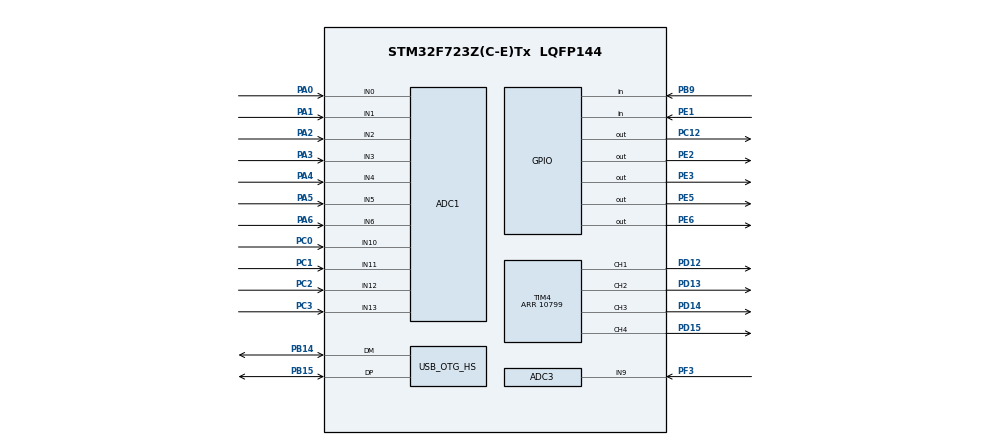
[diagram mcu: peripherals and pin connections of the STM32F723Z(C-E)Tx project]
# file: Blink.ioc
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ADC1.Channel-10\#ChannelRegularConversion=ADC_CHANNEL_2
ADC1.Channel-11\#ChannelRegularConversion=ADC_CHANNEL_3
ADC1.Channel-12\#ChannelRegularConversion=ADC_CHANNEL_4
ADC1.Channel-13\#ChannelRegularConversion=ADC_CHANNEL_5
ADC1.Channel-14\#ChannelRegularConversion=ADC_CHANNEL_10
ADC1.Channel-15\#ChannelRegularConversion=ADC_CHANNEL_11
ADC1.Channel-16\#ChannelRegularConversion=ADC_CHANNEL_12
ADC1.Channel-17\#ChannelRegularConversion=ADC_CHANNEL_6
ADC1.Channel-8\#ChannelRegularConversion=ADC_CHANNEL_0
ADC1.Channel-9\#ChannelRegularConversion=ADC_CHANNEL_1
ADC1.ClockPrescaler=ADC_CLOCK_SYNC_PCLK_DIV8
ADC1.ContinuousConvMode=ENABLE
ADC1.DMAContinuousRequests=ENABLE
ADC1.EOCSelection=ADC_EOC_SEQ_CONV
ADC1.ExternalTrigConv=ADC_SOFTWARE_START
ADC1.InjNumberOfConversion=0
ADC1.NbrOfConversion=10
ADC1.NbrOfConversionFlag=1
ADC1.Rank-10\#ChannelRegularConversion=3
ADC1.Rank-11\#ChannelRegularConversion=4
ADC1.Rank-12\#ChannelRegularConversion=5
ADC1.Rank-13\#ChannelRegularConversion=6
ADC1.Rank-14\#ChannelRegularConversion=7
ADC1.Rank-15\#ChannelRegularConversion=8
ADC1.Rank-16\#ChannelRegularConversion=9
ADC1.Rank-17\#ChannelRegularConversion=10
ADC1.Rank-8\#ChannelRegularConversion=1
ADC1.Rank-9\#ChannelRegularConversion=2
ADC1.SamplingTime-10\#ChannelRegularConversion=ADC_SAMPLETIME_3CYCLES
ADC1.SamplingTime-11\#ChannelRegularConversion=ADC_SAMPLETIME_3CYCLES
ADC1.SamplingTime-12\#ChannelRegularConversion=ADC_SAMPLETIME_3CYCLES
ADC1.SamplingTime-13\#ChannelRegularConversion=ADC_SAMPLETIME_3CYCLES
ADC1.SamplingTime-14\#ChannelRegularConversion=ADC_SAMPLETIME_3CYCLES
ADC1.SamplingTime-15\#ChannelRegularConversion=ADC_SAMPLETIME_3CYCLES
ADC1.SamplingTime-16\#ChannelRegularConversion=ADC_SAMPLETIME_3CYCLES
ADC1.SamplingTime-17\#ChannelRegularConversion=ADC_SAMPLETIME_3CYCLES
ADC1.SamplingTime-8\#ChannelRegularConversion=ADC_SAMPLETIME_3CYCLES
ADC1.SamplingTime-9\#ChannelRegularConversion=ADC_SAMPLETIME_3CYCLES
ADC1.master=1
ADC3.Channel-1\#ChannelRegularConversion=ADC_CHANNEL_9
ADC3.ClockPrescaler=ADC_CLOCK_SYNC_PCLK_DIV8
ADC3.NbrOfConversionFlag=1
ADC3.Rank-1\#ChannelRegularConversion=1
ADC3.SamplingTime-1\#ChannelRegularConversion=ADC_SAMPLETIME_3CYCLES
CORTEX_M7.default_mode_Activation=1
Dma.ADC1.0.Direction=DMA_PERIPH_TO_MEMORY
Dma.ADC1.0.FIFOMode=DMA_FIFOMODE_DISABLE
Dma.ADC1.0.Instance=DMA2_Stream0
Dma.ADC1.0.MemDataAlignment=DMA_MDATAALIGN_HALFWORD
Dma.ADC1.0.MemInc=DMA_MINC_ENABLE
Dma.ADC1.0.Mode=DMA_CIRCULAR
Dma.ADC1.0.PeriphDataAlignment=DMA_PDATAALIGN_HALFWORD
Dma.ADC1.0.PeriphInc=DMA_PINC_DISABLE
Dma.ADC1.0.Priority=DMA_PRIORITY_LOW
Dma.Request0=ADC1
Mcu.Family=STM32F7
Mcu.Name=STM32F723Z(C-E)Tx
Mcu.Package=LQFP144
NVIC.ADC_IRQn=true\:0\:0\:false\:false\:true\:true\:true\:true
NVIC.DMA2_Stream0_IRQn=true\:0\:0\:false\:false\:true\:false\:true\:true
NVIC.OTG_HS_IRQn=true\:0\:0\:false\:false\:true\:true\:true\:true
NVIC.PriorityGroup=NVIC_PRIORITYGROUP_4
NVIC.TIM2_IRQn=true\:0\:0\:false\:false\:true\:true\:true\:true
NVIC.TIM5_IRQn=true\:0\:0\:false\:false\:true\:true\:true\:true
PA0-WKUP.Signal=ADCx_IN0
PA1.Signal=ADCx_IN1
PA13.Mode=Serial_Wire
PA13.Signal=SYS_JTMS-SWDIO
PA14.Mode=Serial_Wire
PA14.Signal=SYS_JTCK-SWCLK
PA2.Signal=ADCx_IN2
PA3.Signal=ADCx_IN3
PA4.Signal=ADCx_IN4
PA5.Signal=ADCx_IN5
PA6.Signal=ADCx_IN6
PB0.Signal=ADCx_IN8
PB14.Mode=Internal_Phy_Device
PB14.Signal=USB_OTG_HS_DM
PB15.Mode=Internal_Phy_Device
PB15.Signal=USB_OTG_HS_DP
PB9.GPIO_PuPd=GPIO_PULLDOWN
PB9.Signal=GPIO_Input
PC0.Signal=ADCx_IN10
PC1.Signal=ADCx_IN11
PC12.Signal=GPIO_Output
PC2.Signal=ADCx_IN12
PC3.Signal=ADCx_IN13
PC4.Signal=ADCx_IN14
PD12.Signal=S_TIM4_CH1
PD13.Signal=S_TIM4_CH2
PD14.Signal=S_TIM4_CH3
PD15.Signal=S_TIM4_CH4
PE1.GPIO_PuPd=GPIO_PULLDOWN
PE1.Signal=GPIO_Input
PE2.Signal=GPIO_Output
PE3.Signal=GPIO_Output
PE5.Signal=GPIO_Output
PE6.Signal=GPIO_Output
PF3.Mode=IN9
PF3.Signal=ADC3_IN9
PH0-OSC_IN.Mode=HSE-External-Oscillator
PH0-OSC_IN.Signal=RCC_OSC_IN
PH1-OSC_OUT.Mode=HSE-External-Oscillator
PH1-OSC_OUT.Signal=RCC_OSC_OUT
ProjectManager.HeapSize=0x200
ProjectManager.StackSize=0x400
ProjectManager.TargetToolchain=Makefile
RCC.AHBFreq_Value=96000000
RCC.APB1CLKDivider=RCC_HCLK_DIV2
RCC.APB1Freq_Value=48000000
RCC.APB1TimFreq_Value=96000000
RCC.APB2Freq_Value=96000000
RCC.APB2TimFreq_Value=96000000
RCC.CortexFreq_Value=96000000
RCC.HCLKFreq_Value=96000000
RCC.HSE_VALUE=12000000
RCC.HSI_VALUE=16000000
RCC.LSE_VALUE=32768
RCC.PLLM=6
RCC.PLLN=96
RCC.PLLQ=4
RCC.SYSCLKFreq_VALUE=96000000
RCC.SYSCLKSource=RCC_SYSCLKSOURCE_PLLCLK
RCC.USBFreq_Value=48000000
RCC.VCOOutputFreq_Value=192000000
REXTPHYHS.Mode=Internal_Phy_Device
REXTPHYHS.Signal=USB_OTG_HS_REXTPHYHS
SH.ADCx_IN0.0=ADC1_IN0,IN0
SH.ADCx_IN1.0=ADC1_IN1,IN1
SH.ADCx_IN10.0=ADC1_IN10,IN10
SH.ADCx_IN11.0=ADC1_IN11,IN11
SH.ADCx_IN12.0=ADC1_IN12,IN12
SH.ADCx_IN13.0=ADC1_IN13,IN13
SH.ADCx_IN14.0=ADC1_IN14
SH.ADCx_IN2.0=ADC1_IN2,IN2
SH.ADCx_IN3.0=ADC2_IN3
SH.ADCx_IN3.1=ADC1_IN3,IN3
SH.ADCx_IN4.0=ADC2_IN4
SH.ADCx_IN4.1=ADC1_IN4,IN4
SH.ADCx_IN5.0=ADC1_IN5,IN5
SH.ADCx_IN6.0=ADC1_IN6,IN6
SH.ADCx_IN8.0=ADC1_IN8
SH.S_TIM4_CH1.0=TIM4_CH1,PWM Generation1 CH1
SH.S_TIM4_CH2.0=TIM4_CH2,PWM Generation2 CH2
SH.S_TIM4_CH3.0=TIM4_CH3,PWM Generation3 CH3
SH.S_TIM4_CH4.0=TIM4_CH4,PWM Generation4 CH4
TIM2.Period=5399
TIM4.Channel-PWM\ Generation1\ CH1=TIM_CHANNEL_1
TIM4.Channel-PWM\ Generation2\ CH2=TIM_CHANNEL_2
TIM4.Channel-PWM\ Generation3\ CH3=TIM_CHANNEL_3
TIM4.Channel-PWM\ Generation4\ CH4=TIM_CHANNEL_4
TIM4.Period=10799
TIM5.Period=216000
TIM5.TIM_MasterOutputTrigger=TIM_TRGO_UPDATE
USB_OTG_HS.VirtualMode=Int_Phy_Device
VP_TIM2_VS_ClockSourceINT.Mode=Internal
VP_TIM5_VS_ClockSourceINT.Mode=Internal
board=custom

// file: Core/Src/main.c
/* USER CODE BEGIN Header */
/**
  ******************************************************************************
  * @file           : main.c
  * @brief          : Main program body
  ******************************************************************************
  * @attention
  *
  * Copyright (c) 2024 STMicroelectronics.
  * All rights reserved.
  *
  * This software is licensed under terms that can be found in the LICENSE file
  * in the root directory of this software component.
  * If no LICENSE file comes with this software, it is provided AS-IS.
  *
  ******************************************************************************
  */
/* USER CODE END Header */
#include "main.h"

/* USER CODE BEGIN Includes */

#include "device/usbd_pvt.h"
#include "stm32f7xx_hal_adc.h"
#include "stm32f7xx_hal_def.h"

#include "motor.h"
#include "controller.h"
#include "stm32f7xx_hal_tim.h"

#include "arm_math.h"
#include <stdint.h>

#include "tusb_config.h"
#include "tusb.h"
#include "SEGGER_RTT.h"

/* USER CODE END Includes */

ADC_HandleTypeDef hadc1;
ADC_HandleTypeDef hadc3;
DMA_HandleTypeDef hdma_adc1;

TIM_HandleTypeDef htim2;
TIM_HandleTypeDef htim4;
TIM_HandleTypeDef htim5;

PCD_HandleTypeDef hpcd_USB_OTG_HS;

/* USER CODE BEGIN PV */

// DELETE SOON

// float pwmCommand1 = 0;
// float current1 = 0;
// const float k = 0.34/6.9;
// float T1_Read;
// float T1_Set;
// float error;
float theta1;
float theta2;
float current1;
float current2;
float W1;
float W2;
float pwm1;
float pwm2;
float pwm_command;

volatile float torqueSet;
float T2;
float T3;

//Grav Comp on/off 1/0
commands_t controllerStatus;

//text

// Variable Definition

/* USER CODE END PV */

void SystemClock_Config(void);
static void MPU_Config(void);
static void MX_GPIO_Init(void);
static void MX_DMA_Init(void);
static void MX_ADC3_Init(void);
static void MX_TIM4_Init(void);
static void MX_ADC1_Init(void);
static void MX_TIM2_Init(void);
static void MX_TIM5_Init(void);
static void MX_USB_OTG_HS_PCD_Init(void);
/* USER CODE BEGIN PFP */
int16_t DMA_buffer[10];

// CONTROLLER
controller_t controller1 = {
  .J1 =
  {

  .htim = &htim4,
  .pwm_channel = TIM_CHANNEL_4,
  .dir_port = GPIOE,
  .motorDir = 1,
  .dir_pin = GPIO_PIN_3,
  .fault_port = GPIOE,
  .fault_pin = GPIO_PIN_2,

  .positionCounts = &DMA_buffer[3],
  .currentCounts = &DMA_buffer[6],

  .angle_range = -45.0f,
  .angle_start = 2053.0f,
  .angle_end = 1480.0f,

  .Rsense = 0.01081,
  .frictionGain = 0.8127,
  .frictionOffset = 1.6,

   .pid =
    {
      .kp = 0.01,
      .ki = 0.02,
      .kd = 0,
      .processMax = 1,
      .processMin = 0
    }
  },

  .J2 =
  {
  .htim = &htim4,
  .pwm_channel = TIM_CHANNEL_4,
  .dir_port = GPIOE,
  .dir_pin = GPIO_PIN_3,
  .motorDir = 1,
  .fault_port = GPIOE,
  .fault_pin = GPIO_PIN_2,

  .positionCounts = &DMA_buffer[0],
  .currentCounts = &DMA_buffer[6],

  .Rsense = 0.01752467,
  .frictionGain = 0.1473,
  .frictionOffset = 1.1673,

  .angle_range = 90.0f,
  .angle_start = 2051.0f,
  .angle_end = 964.0f,

  .pid =
    {
      .kp = 0.01,
      .ki = 0.02,
      .kd = 0,
      .processMax = 1,
      .processMin = 0.01
    }
  },

  .J3 =
  {
  .htim = &htim4,
  .pwm_channel = TIM_CHANNEL_2,
  .dir_port = GPIOC,
  .dir_pin = GPIO_PIN_15,
  .motorDir = 1,

  .positionCounts = &DMA_buffer[2],
  .currentCounts = &DMA_buffer[8],

  .Rsense = 0.019512,
  .frictionGain = 0.1946,
  .frictionOffset = 0.86,

  .angle_range = -90.0f,
  .angle_start = 3087.0f,
  .angle_end = 2066.0f,

  .pid =
    {
      .kp = 0.01,
      .ki = 0.02,
      .kd = 0,
      .processMax = 1,
      .processMin = 0.01
    }
  },

  .J4 =
  {
  .htim = &htim4,
  .pwm_channel = TIM_CHANNEL_1,
  .dir_port = GPIOF,
  .dir_pin = GPIO_PIN_2,
  .motorDir = 1,

  .positionCounts = &DMA_buffer[4],

  .angle_range = -90.0f,
  .angle_start = 1719.0f,
  .angle_end = 605.0f,

  // .pid =
  //   {
  //     .kp = 0.3,
  //     .ki = 0.01,
  //     .kd = 0,
  //     .processMax = 1,
  //     .processMin = 0.01
  //   }
  },

  .J5 =
  {
  .htim = &htim4,
  .pwm_channel = TIM_CHANNEL_2,
  .dir_port = GPIOE,
  .dir_pin = GPIO_PIN_6,

  .positionCounts = &DMA_buffer[4],
  // .currentCounts = &DMA_buffer[12],

  // .theta_current = 0,
  // .angle_range = -90.0f,
  // .angle_start = 1012.0f,
  // .angle_end = 1977.0f,

  // .pid =
  //   {
  //     .kp = 0.3,
  //     .ki = 0.01,
  //     .kd = 0,
  //     .processMax = 1,
  //     .processMin = 0.01
  //   }
  },

  .J6 =
  {
  // .htim = &htim4,
  // .pwm_channel = TIM_CHANNEL_2,
  // .dir_port = GPIOE,
  // .dir_pin = GPIO_PIN_6,

  .positionCounts = &DMA_buffer[5],
  // .currentCounts = &DMA_buffer[12],

  // .theta_current = 0,
  // .angle_range = -90.0f,
  // .angle_start = 1012.0f,
  // .angle_end = 1977.0f,

  // .pid =
  //   {
  //     .kp = 0.3,
  //     .ki = 0.01,
  //     .kd = 0,
  //     .processMax = 1,
  //     .processMin = 0.01
  //   }
  },
  .gc_scale_T2 = 0.4,
  .gc_scale_T3 = 0.4,

  //Button Inputs
  .raw_trigger_reading = &DMA_buffer[5],
  .clutch_port = GPIOB,
  .clutch_pin = GPIO_PIN_9,
  .trigger_on = 2000.0f,
  .trigger_zero = 2400.0f,

  .frameScale = 0.3,

  .homeX = 0,
  .homeY = 0,
  .homeZ = 370.0f,

  .miraXoff = 0,
  .miraYoff = -28,
  .miraZoff = -50,

  .pitchOffset = 15.0

};

/* USER CODE END PFP */

/* USER CODE BEGIN 0 */

// // Function - USB Blocking
// USBD_StatusTypeDef CDC_Transmit_HS_Blocking(uint8_t* Buf, uint16_t Len) {
//     USBD_StatusTypeDef result = USBD_BUSY;

//     // Keep attempting to transmit until USBD_OK is returned
//     while (result != USBD_OK) {
//         result = CDC_Transmit_HS(Buf, Len);

//         // Optionally add a small delay to avoid CPU overload
//         HAL_Delay(1);
//     }

//     return result;
// }
uint8_t rtt_buffer[1024];

typedef struct {

  commands_t gc_status;

  // float j1_torque;
  // float j2_torque;
  // float j3_torque;
} setpoint_cmd_t;

typedef struct __attribute__((packed)) {
  float x;
  float y;
  float z;
  float pitch;
  float trigger;

  uint8_t clutch_status;

} armstatus_t;

/* USER CODE END 0 */

int main(void)
{

  /* USER CODE BEGIN 1 */
  SEGGER_RTT_ConfigUpBuffer(0, NULL, rtt_buffer, sizeof(rtt_buffer), SEGGER_RTT_MODE_NO_BLOCK_SKIP);

  printf("hello again");
  /* USER CODE END 1 */

  /* MPU Configuration--------------------------------------------------------*/
  MPU_Config();

  /* MCU Configuration--------------------------------------------------------*/

  /* Reset of all peripherals, Initializes the Flash interface and the Systick. */
  HAL_Init();

  /* Configure the system clock */
  SystemClock_Config();

  /* Initialize all configured peripherals */
  MX_GPIO_Init();
  MX_DMA_Init();
  MX_ADC3_Init();
  MX_TIM4_Init();
  MX_ADC1_Init();
  MX_TIM2_Init();
  MX_TIM5_Init();
  MX_USB_OTG_HS_PCD_Init();
  /* USER CODE BEGIN 2 */

__HAL_RCC_USB_OTG_HS_CLK_ENABLE();
tud_init(BOARD_TUD_RHPORT);

  // HAL_TIM_Base_Start(&htim2);

  HAL_TIM_PWM_Start(&htim4,TIM_CHANNEL_1);
  HAL_TIM_PWM_Start(&htim4,TIM_CHANNEL_2);
  HAL_TIM_PWM_Start(&htim4,TIM_CHANNEL_3);
  HAL_TIM_PWM_Start(&htim4,TIM_CHANNEL_4);

  HAL_TIM_Base_Start_IT(&htim5);

  // HAL_TIM_PWM_Start(&htim4,TIM_CHANNEL_3);

  HAL_GPIO_WritePin(GPIOE, GPIO_PIN_2, GPIO_PIN_SET);

  // HAL_TIM_Base_Start_IT(&htim5);
  HAL_ADC_Start_DMA(&hadc1, (uint32_t*)DMA_buffer, 10);
  // HAL_ADC_Start_DMA(&hadc2, (uint32_t*)(DMA_buffer+5), 3);

  /* USER CODE END 2 */

  /* Infinite loop */
  /* USER CODE BEGIN WHILE */
  while (1)
  {

  // float angleCorrection = controller1.J1.theta_current;

  // controller1.J2.pwmCommand = pwm_command * cos(-angleCorrection * PI/180.0f);
// currentSet = 0.5;
  // pwm_set(&controller1.J1,pwm_command,1);
  // pwm_set(&controller1.J2,pwm_command,1);
  // pwm_set(&controller1.J3,pwm_command,1);
  // pwm_set(&controller1.J4,pwm_command,1);

  tud_task();
    /* USER CODE END WHILE */

  }
}

void SystemClock_Config(void)
{
  RCC_OscInitTypeDef RCC_OscInitStruct = {0};
  RCC_ClkInitTypeDef RCC_ClkInitStruct = {0};

  /** Configure the main internal regulator output voltage
  */
  __HAL_RCC_PWR_CLK_ENABLE();
  __HAL_PWR_VOLTAGESCALING_CONFIG(PWR_REGULATOR_VOLTAGE_SCALE1);

  /** Initializes the RCC Oscillators according to the specified parameters
  * in the RCC_OscInitTypeDef structure.
  */
  RCC_OscInitStruct.OscillatorType = RCC_OSCILLATORTYPE_HSE;
  RCC_OscInitStruct.HSEState = RCC_HSE_ON;
  RCC_OscInitStruct.PLL.PLLState = RCC_PLL_ON;
  RCC_OscInitStruct.PLL.PLLSource = RCC_PLLSOURCE_HSE;
  RCC_OscInitStruct.PLL.PLLM = 6;
  RCC_OscInitStruct.PLL.PLLN = 216;
  RCC_OscInitStruct.PLL.PLLP = RCC_PLLP_DIV2;
  RCC_OscInitStruct.PLL.PLLQ = 9;
  if (HAL_RCC_OscConfig(&RCC_OscInitStruct) != HAL_OK)
  {
    Error_Handler();
  }

  /** Activate the Over-Drive mode
  */
  if (HAL_PWREx_EnableOverDrive() != HAL_OK)
  {
    Error_Handler();
  }

  /** Initializes the CPU, AHB and APB buses clocks
  */
  RCC_ClkInitStruct.ClockType = RCC_CLOCKTYPE_HCLK|RCC_CLOCKTYPE_SYSCLK
                              |RCC_CLOCKTYPE_PCLK1|RCC_CLOCKTYPE_PCLK2;
  RCC_ClkInitStruct.SYSCLKSource = RCC_SYSCLKSOURCE_PLLCLK;
  RCC_ClkInitStruct.AHBCLKDivider = RCC_SYSCLK_DIV1;
  RCC_ClkInitStruct.APB1CLKDivider = RCC_HCLK_DIV4;
  RCC_ClkInitStruct.APB2CLKDivider = RCC_HCLK_DIV2;

  if (HAL_RCC_ClockConfig(&RCC_ClkInitStruct, FLASH_LATENCY_7) != HAL_OK)
  {
    Error_Handler();
  }
}

static void MX_ADC1_Init(void)
{

  ADC_ChannelConfTypeDef sConfig = {0};

  /** Configure the global features of the ADC (Clock, Resolution, Data Alignment and number of conversion)
  */
  hadc1.Instance = ADC1;
  hadc1.Init.ClockPrescaler = ADC_CLOCK_SYNC_PCLK_DIV8;
  hadc1.Init.Resolution = ADC_RESOLUTION_12B;
  hadc1.Init.ScanConvMode = ADC_SCAN_ENABLE;
  hadc1.Init.ContinuousConvMode = ENABLE;
  hadc1.Init.DiscontinuousConvMode = DISABLE;
  hadc1.Init.ExternalTrigConvEdge = ADC_EXTERNALTRIGCONVEDGE_NONE;
  hadc1.Init.ExternalTrigConv = ADC_SOFTWARE_START;
  hadc1.Init.DataAlign = ADC_DATAALIGN_RIGHT;
  hadc1.Init.NbrOfConversion = 10;
  hadc1.Init.DMAContinuousRequests = ENABLE;
  hadc1.Init.EOCSelection = ADC_EOC_SEQ_CONV;
  if (HAL_ADC_Init(&hadc1) != HAL_OK)
  {
    Error_Handler();
  }

  /** Configure for the selected ADC regular channel its corresponding rank in the sequencer and its sample time.
  */
  sConfig.Channel = ADC_CHANNEL_0;
  sConfig.Rank = ADC_REGULAR_RANK_1;
  sConfig.SamplingTime = ADC_SAMPLETIME_3CYCLES;
  if (HAL_ADC_ConfigChannel(&hadc1, &sConfig) != HAL_OK)
  {
    Error_Handler();
  }

  /** Configure for the selected ADC regular channel its corresponding rank in the sequencer and its sample time.
  */
  sConfig.Channel = ADC_CHANNEL_1;
  sConfig.Rank = ADC_REGULAR_RANK_2;
  if (HAL_ADC_ConfigChannel(&hadc1, &sConfig) != HAL_OK)
  {
    Error_Handler();
  }

  /** Configure for the selected ADC regular channel its corresponding rank in the sequencer and its sample time.
  */
  sConfig.Channel = ADC_CHANNEL_2;
  sConfig.Rank = ADC_REGULAR_RANK_3;
  if (HAL_ADC_ConfigChannel(&hadc1, &sConfig) != HAL_OK)
  {
    Error_Handler();
  }

  /** Configure for the selected ADC regular channel its corresponding rank in the sequencer and its sample time.
  */
  sConfig.Channel = ADC_CHANNEL_3;
  sConfig.Rank = ADC_REGULAR_RANK_4;
  if (HAL_ADC_ConfigChannel(&hadc1, &sConfig) != HAL_OK)
  {
    Error_Handler();
  }

  /** Configure for the selected ADC regular channel its corresponding rank in the sequencer and its sample time.
  */
  sConfig.Channel = ADC_CHANNEL_4;
  sConfig.Rank = ADC_REGULAR_RANK_5;
  if (HAL_ADC_ConfigChannel(&hadc1, &sConfig) != HAL_OK)
  {
    Error_Handler();
  }

  /** Configure for the selected ADC regular channel its corresponding rank in the sequencer and its sample time.
  */
  sConfig.Channel = ADC_CHANNEL_5;
  sConfig.Rank = ADC_REGULAR_RANK_6;
  if (HAL_ADC_ConfigChannel(&hadc1, &sConfig) != HAL_OK)
  {
    Error_Handler();
  }

  /** Configure for the selected ADC regular channel its corresponding rank in the sequencer and its sample time.
  */
  sConfig.Channel = ADC_CHANNEL_10;
  sConfig.Rank = ADC_REGULAR_RANK_7;
  if (HAL_ADC_ConfigChannel(&hadc1, &sConfig) != HAL_OK)
  {
    Error_Handler();
  }

  /** Configure for the selected ADC regular channel its corresponding rank in the sequencer and its sample time.
  */
  sConfig.Channel = ADC_CHANNEL_11;
  sConfig.Rank = ADC_REGULAR_RANK_8;
  if (HAL_ADC_ConfigChannel(&hadc1, &sConfig) != HAL_OK)
  {
    Error_Handler();
  }

  /** Configure for the selected ADC regular channel its corresponding rank in the sequencer and its sample time.
  */
  sConfig.Channel = ADC_CHANNEL_12;
  sConfig.Rank = ADC_REGULAR_RANK_9;
  if (HAL_ADC_ConfigChannel(&hadc1, &sConfig) != HAL_OK)
  {
    Error_Handler();
  }

  /** Configure for the selected ADC regular channel its corresponding rank in the sequencer and its sample time.
  */
  sConfig.Channel = ADC_CHANNEL_6;
  sConfig.Rank = ADC_REGULAR_RANK_10;
  if (HAL_ADC_ConfigChannel(&hadc1, &sConfig) != HAL_OK)
  {
    Error_Handler();
  }
  /* USER CODE BEGIN ADC1_Init 2 */

  //Configure Channel 0
  sConfig.Channel = ADC_CHANNEL_0;
  sConfig.Rank = ADC_REGULAR_RANK_1;
  sConfig.SamplingTime = ADC_SAMPLETIME_3CYCLES;
  HAL_ADC_ConfigChannel(&hadc1, &sConfig);

  //Configure Channel 10
  sConfig.Channel = ADC_CHANNEL_10;
  sConfig.Rank = ADC_REGULAR_RANK_2;
  HAL_ADC_ConfigChannel(&hadc1, &sConfig);

  /* USER CODE END ADC1_Init 2 */

}

static void MX_ADC3_Init(void)
{

  ADC_ChannelConfTypeDef sConfig = {0};

  /** Configure the global features of the ADC (Clock, Resolution, Data Alignment and number of conversion)
  */
  hadc3.Instance = ADC3;
  hadc3.Init.ClockPrescaler = ADC_CLOCK_SYNC_PCLK_DIV8;
  hadc3.Init.Resolution = ADC_RESOLUTION_12B;
  hadc3.Init.ScanConvMode = ADC_SCAN_DISABLE;
  hadc3.Init.ContinuousConvMode = DISABLE;
  hadc3.Init.DiscontinuousConvMode = DISABLE;
  hadc3.Init.ExternalTrigConvEdge = ADC_EXTERNALTRIGCONVEDGE_NONE;
  hadc3.Init.ExternalTrigConv = ADC_SOFTWARE_START;
  hadc3.Init.DataAlign = ADC_DATAALIGN_RIGHT;
  hadc3.Init.NbrOfConversion = 1;
  hadc3.Init.DMAContinuousRequests = DISABLE;
  hadc3.Init.EOCSelection = ADC_EOC_SINGLE_CONV;
  if (HAL_ADC_Init(&hadc3) != HAL_OK)
  {
    Error_Handler();
  }

  /** Configure for the selected ADC regular channel its corresponding rank in the sequencer and its sample time.
  */
  sConfig.Channel = ADC_CHANNEL_9;
  sConfig.Rank = ADC_REGULAR_RANK_1;
  sConfig.SamplingTime = ADC_SAMPLETIME_3CYCLES;
  if (HAL_ADC_ConfigChannel(&hadc3, &sConfig) != HAL_OK)
  {
    Error_Handler();
  }

}

static void MX_TIM2_Init(void)
{

  TIM_ClockConfigTypeDef sClockSourceConfig = {0};
  TIM_MasterConfigTypeDef sMasterConfig = {0};

  htim2.Instance = TIM2;
  htim2.Init.Prescaler = 0;
  htim2.Init.CounterMode = TIM_COUNTERMODE_UP;
  htim2.Init.Period = 5399;
  htim2.Init.ClockDivision = TIM_CLOCKDIVISION_DIV1;
  htim2.Init.AutoReloadPreload = TIM_AUTORELOAD_PRELOAD_DISABLE;
  if (HAL_TIM_Base_Init(&htim2) != HAL_OK)
  {
    Error_Handler();
  }
  sClockSourceConfig.ClockSource = TIM_CLOCKSOURCE_INTERNAL;
  if (HAL_TIM_ConfigClockSource(&htim2, &sClockSourceConfig) != HAL_OK)
  {
    Error_Handler();
  }
  sMasterConfig.MasterOutputTrigger = TIM_TRGO_RESET;
  sMasterConfig.MasterSlaveMode = TIM_MASTERSLAVEMODE_DISABLE;
  if (HAL_TIMEx_MasterConfigSynchronization(&htim2, &sMasterConfig) != HAL_OK)
  {
    Error_Handler();
  }

}

static void MX_TIM4_Init(void)
{

  TIM_MasterConfigTypeDef sMasterConfig = {0};
  TIM_OC_InitTypeDef sConfigOC = {0};

  htim4.Instance = TIM4;
  htim4.Init.Prescaler = 0;
  htim4.Init.CounterMode = TIM_COUNTERMODE_UP;
  htim4.Init.Period = 10799;
  htim4.Init.ClockDivision = TIM_CLOCKDIVISION_DIV1;
  htim4.Init.AutoReloadPreload = TIM_AUTORELOAD_PRELOAD_DISABLE;
  if (HAL_TIM_PWM_Init(&htim4) != HAL_OK)
  {
    Error_Handler();
  }
  sMasterConfig.MasterOutputTrigger = TIM_TRGO_RESET;
  sMasterConfig.MasterSlaveMode = TIM_MASTERSLAVEMODE_DISABLE;
  if (HAL_TIMEx_MasterConfigSynchronization(&htim4, &sMasterConfig) != HAL_OK)
  {
    Error_Handler();
  }
  sConfigOC.OCMode = TIM_OCMODE_PWM1;
  sConfigOC.Pulse = 0;
  sConfigOC.OCPolarity = TIM_OCPOLARITY_HIGH;
  sConfigOC.OCFastMode = TIM_OCFAST_DISABLE;
  if (HAL_TIM_PWM_ConfigChannel(&htim4, &sConfigOC, TIM_CHANNEL_1) != HAL_OK)
  {
    Error_Handler();
  }
  if (HAL_TIM_PWM_ConfigChannel(&htim4, &sConfigOC, TIM_CHANNEL_2) != HAL_OK)
  {
    Error_Handler();
  }
  if (HAL_TIM_PWM_ConfigChannel(&htim4, &sConfigOC, TIM_CHANNEL_3) != HAL_OK)
  {
    Error_Handler();
  }
  if (HAL_TIM_PWM_ConfigChannel(&htim4, &sConfigOC, TIM_CHANNEL_4) != HAL_OK)
  {
    Error_Handler();
  }
  HAL_TIM_MspPostInit(&htim4);

}

static void MX_TIM5_Init(void)
{

  TIM_ClockConfigTypeDef sClockSourceConfig = {0};
  TIM_MasterConfigTypeDef sMasterConfig = {0};

  htim5.Instance = TIM5;
  htim5.Init.Prescaler = 0;
  htim5.Init.CounterMode = TIM_COUNTERMODE_UP;
  htim5.Init.Period = 216000;
  htim5.Init.ClockDivision = TIM_CLOCKDIVISION_DIV1;
  htim5.Init.AutoReloadPreload = TIM_AUTORELOAD_PRELOAD_DISABLE;
  if (HAL_TIM_Base_Init(&htim5) != HAL_OK)
  {
    Error_Handler();
  }
  sClockSourceConfig.ClockSource = TIM_CLOCKSOURCE_INTERNAL;
  if (HAL_TIM_ConfigClockSource(&htim5, &sClockSourceConfig) != HAL_OK)
  {
    Error_Handler();
  }
  sMasterConfig.MasterOutputTrigger = TIM_TRGO_UPDATE;
  sMasterConfig.MasterSlaveMode = TIM_MASTERSLAVEMODE_DISABLE;
  if (HAL_TIMEx_MasterConfigSynchronization(&htim5, &sMasterConfig) != HAL_OK)
  {
    Error_Handler();
  }

}

static void MX_USB_OTG_HS_PCD_Init(void)
{

  hpcd_USB_OTG_HS.Instance = USB_OTG_HS;
  hpcd_USB_OTG_HS.Init.dev_endpoints = 9;
  hpcd_USB_OTG_HS.Init.dma_enable = DISABLE;
  hpcd_USB_OTG_HS.Init.phy_itface = USB_OTG_HS_EMBEDDED_PHY;
  hpcd_USB_OTG_HS.Init.Sof_enable = DISABLE;
  hpcd_USB_OTG_HS.Init.low_power_enable = DISABLE;
  hpcd_USB_OTG_HS.Init.lpm_enable = DISABLE;
  hpcd_USB_OTG_HS.Init.vbus_sensing_enable = DISABLE;
  hpcd_USB_OTG_HS.Init.use_dedicated_ep1 = DISABLE;
  hpcd_USB_OTG_HS.Init.use_external_vbus = DISABLE;
  if (HAL_PCD_Init(&hpcd_USB_OTG_HS) != HAL_OK)
  {
    Error_Handler();
  }

}

static void MX_DMA_Init(void)
{

  /* DMA controller clock enable */
  __HAL_RCC_DMA2_CLK_ENABLE();

  /* DMA interrupt init */
  /* DMA2_Stream0_IRQn interrupt configuration */
  HAL_NVIC_SetPriority(DMA2_Stream0_IRQn, 0, 0);
  HAL_NVIC_EnableIRQ(DMA2_Stream0_IRQn);

}

static void MX_GPIO_Init(void)
{
  GPIO_InitTypeDef GPIO_InitStruct = {0};

  /* GPIO Ports Clock Enable */
  __HAL_RCC_GPIOE_CLK_ENABLE();
  __HAL_RCC_GPIOF_CLK_ENABLE();
  __HAL_RCC_GPIOH_CLK_ENABLE();
  __HAL_RCC_GPIOC_CLK_ENABLE();
  __HAL_RCC_GPIOA_CLK_ENABLE();
  __HAL_RCC_GPIOB_CLK_ENABLE();
  __HAL_RCC_GPIOD_CLK_ENABLE();

  /*Configure GPIO pin Output Level */
  HAL_GPIO_WritePin(GPIOE, GPIO_PIN_2|GPIO_PIN_3|GPIO_PIN_5|GPIO_PIN_6, GPIO_PIN_RESET);

  /*Configure GPIO pin Output Level */
  HAL_GPIO_WritePin(GPIOC, GPIO_PIN_12, GPIO_PIN_RESET);

  /*Configure GPIO pins : PE2 PE3 PE5 PE6 */
  GPIO_InitStruct.Pin = GPIO_PIN_2|GPIO_PIN_3|GPIO_PIN_5|GPIO_PIN_6;
  GPIO_InitStruct.Mode = GPIO_MODE_OUTPUT_PP;
  GPIO_InitStruct.Pull = GPIO_NOPULL;
  GPIO_InitStruct.Speed = GPIO_SPEED_FREQ_LOW;
  HAL_GPIO_Init(GPIOE, &GPIO_InitStruct);

  /*Configure GPIO pins : PA3 PA4 */
  GPIO_InitStruct.Pin = GPIO_PIN_3|GPIO_PIN_4;
  GPIO_InitStruct.Mode = GPIO_MODE_ANALOG;
  GPIO_InitStruct.Pull = GPIO_NOPULL;
  HAL_GPIO_Init(GPIOA, &GPIO_InitStruct);

  /*Configure GPIO pin : PC12 */
  GPIO_InitStruct.Pin = GPIO_PIN_12;
  GPIO_InitStruct.Mode = GPIO_MODE_OUTPUT_PP;
  GPIO_InitStruct.Pull = GPIO_NOPULL;
  GPIO_InitStruct.Speed = GPIO_SPEED_FREQ_LOW;
  HAL_GPIO_Init(GPIOC, &GPIO_InitStruct);

  /*Configure GPIO pin : PB9 */
  GPIO_InitStruct.Pin = GPIO_PIN_9;
  GPIO_InitStruct.Mode = GPIO_MODE_INPUT;
  GPIO_InitStruct.Pull = GPIO_PULLDOWN;
  HAL_GPIO_Init(GPIOB, &GPIO_InitStruct);

  /*Configure GPIO pin : PE1 */
  GPIO_InitStruct.Pin = GPIO_PIN_1;
  GPIO_InitStruct.Mode = GPIO_MODE_INPUT;
  GPIO_InitStruct.Pull = GPIO_PULLDOWN;
  HAL_GPIO_Init(GPIOE, &GPIO_InitStruct);

}

/* USER CODE BEGIN 4 */

// Invoked when received GET DEVICE DESCRIPTOR request
// Application return pointer to descriptor
// uint8_t const * tud_descriptor_device_cb(void) {

// return NULL;
// }

// Invoked when received GET CONFIGURATION DESCRIPTOR request
// Application return pointer to descriptor, whose contents must exist long enough for transfer to complete
// uint8_t const * tud_descriptor_configuration_cb(uint8_t index){

// return NULL;
// }

// Invoked when received GET STRING DESCRIPTOR request
// // Application return pointer to descriptor, whose contents must exist long enough for transfer to complete
// uint16_t const* tud_descriptor_string_cb(uint8_t index, uint16_t langid){

// return NULL;
// }

// Invoked when received GET BOS DESCRIPTOR request
// Application return pointer to descriptor
uint8_t const * tud_descriptor_bos_cb(void){

return NULL;
}

// Invoked when received GET DEVICE QUALIFIER DESCRIPTOR request
// Application return pointer to descriptor, whose contents must exist long enough for transfer to complete.
// device_qualifier descriptor describes information about a high-speed capable device that would
// change if the device were operating at the other speed. If not highspeed capable stall this request.
// uint8_t const* tud_descriptor_device_qualifier_cb(void){

// return NULL;
// }

// Invoked when received GET OTHER SEED CONFIGURATION DESCRIPTOR request
// Application return pointer to descriptor, whose contents must exist long enough for transfer to complete
// Configuration descriptor in the other speed e.g if high speed then this is for full speed and vice versa
// uint8_t const* tud_descriptor_other_speed_configuration_cb(uint8_t index){

// return NULL;
// }
#define BULK_EP_SIZE       64    // Endpoint size

// Buffer for incoming data
uint8_t bulk_out_buffer[BULK_EP_SIZE];

// Buffer for outgoing data
uint8_t bulk_in_buffer[BULK_EP_SIZE] = "Hello from TinyUSB";

void tud_vendor_rx_cb(uint8_t itf, uint8_t const* buffer, uint16_t bufsize)
{
//Data IN
  setpoint_cmd_t cmd;
  memcpy(&cmd, buffer, sizeof(setpoint_cmd_t));
  tud_vendor_read_flush(); // unstall the IN endpoint

//Toggle on/off grav comp;
  controller1.gc_status = cmd.gc_status;

  // printf("Received setpoint! j1 = %f, j2 = %f, j3 = %f",
  // cmd.j1_torque,
  // cmd.j2_torque,
  // cmd.j3_torque);

  // motorSet.motors[0].pid.setpoint = cmd.j1_torque;
  // motorSet.motors[1].pid.setpoint = cmd.j2_torque;
  // motorSet.motors[2].pid.setpoint = cmd.j3_torque;

// Data Out
  armstatus_t data;
  data.x = controller1.x;
  data.y = controller1.y;
  data.z = controller1.z;
  data.pitch = controller1.pitch;
  data.trigger = controller1.trigger_normal;

  data.clutch_status = controller1.clutch_status;

  // printf("received data");
  volatile int size = sizeof(armstatus_t);
  tud_vendor_write(&data,sizeof(armstatus_t));
  tud_vendor_n_write_flush(0);

}

// Invoked when device is mounted (configured)
void tud_mount_cb(void){

}

// Invoked when device is unmounted
void tud_umount_cb(void){

}

// Invoked when usb bus is suspended
// Within 7ms, device must draw an average of current less than 2.5 mA from bus
void tud_suspend_cb(bool remote_wakeup_en){

}

// Invoked when usb bus is resumed
void tud_resume_cb(void){

}

// Invoked when there is a new usb event, which need to be processed by tud_task()/tud_task_ext()
void tud_event_hook_cb(uint8_t rhport, uint32_t eventid, bool in_isr){

}

// Invoked when a new (micro) frame started
void tud_sof_cb(uint32_t frame_count){

}

// Invoked when received control request with VENDOR TYPE
bool tud_vendor_control_xfer_cb(uint8_t rhport, uint8_t stage, tusb_control_request_t const * request){

return NULL;
}

/* USER CODE END 4 */

 /* MPU Configuration */

void MPU_Config(void)
{
  MPU_Region_InitTypeDef MPU_InitStruct = {0};

  /* Disables the MPU */
  HAL_MPU_Disable();

  /** Initializes and configures the Region and the memory to be protected
  */
  MPU_InitStruct.Enable = MPU_REGION_ENABLE;
  MPU_InitStruct.Number = MPU_REGION_NUMBER0;
  MPU_InitStruct.BaseAddress = 0x0;
  MPU_InitStruct.Size = MPU_REGION_SIZE_4GB;
  MPU_InitStruct.SubRegionDisable = 0x87;
  MPU_InitStruct.TypeExtField = MPU_TEX_LEVEL0;
  MPU_InitStruct.AccessPermission = MPU_REGION_NO_ACCESS;
  MPU_InitStruct.DisableExec = MPU_INSTRUCTION_ACCESS_DISABLE;
  MPU_InitStruct.IsShareable = MPU_ACCESS_SHAREABLE;
  MPU_InitStruct.IsCacheable = MPU_ACCESS_NOT_CACHEABLE;
  MPU_InitStruct.IsBufferable = MPU_ACCESS_NOT_BUFFERABLE;

  HAL_MPU_ConfigRegion(&MPU_InitStruct);
  /* Enables the MPU */
  HAL_MPU_Enable(MPU_PRIVILEGED_DEFAULT);

}

void Error_Handler(void)
{

  __disable_irq();
  while (1)
  {
  }
}
